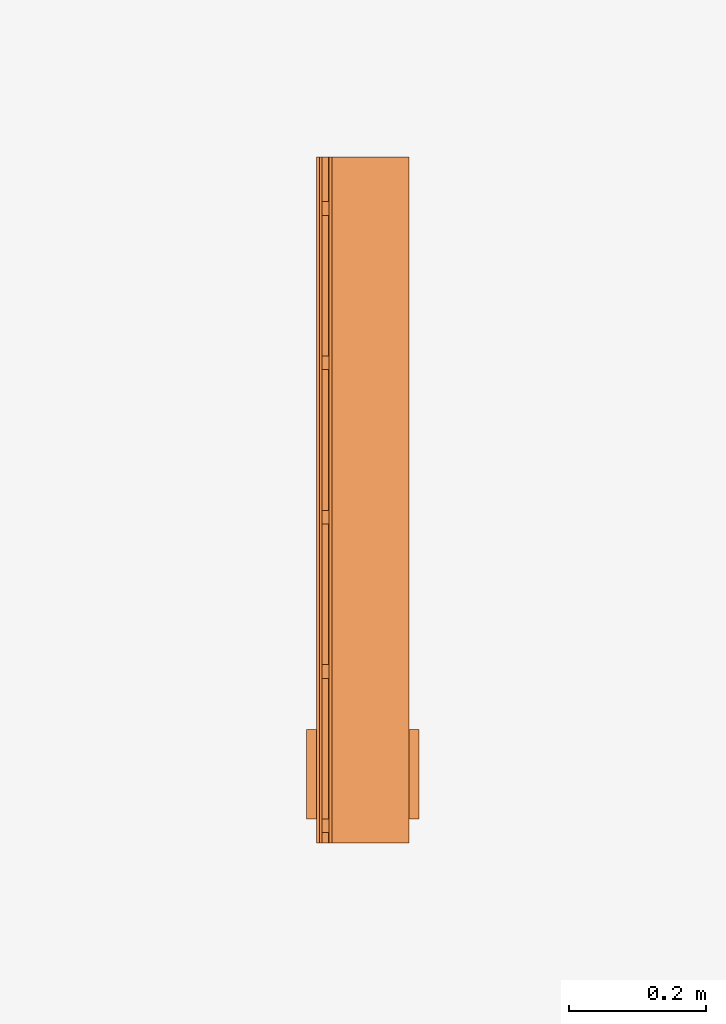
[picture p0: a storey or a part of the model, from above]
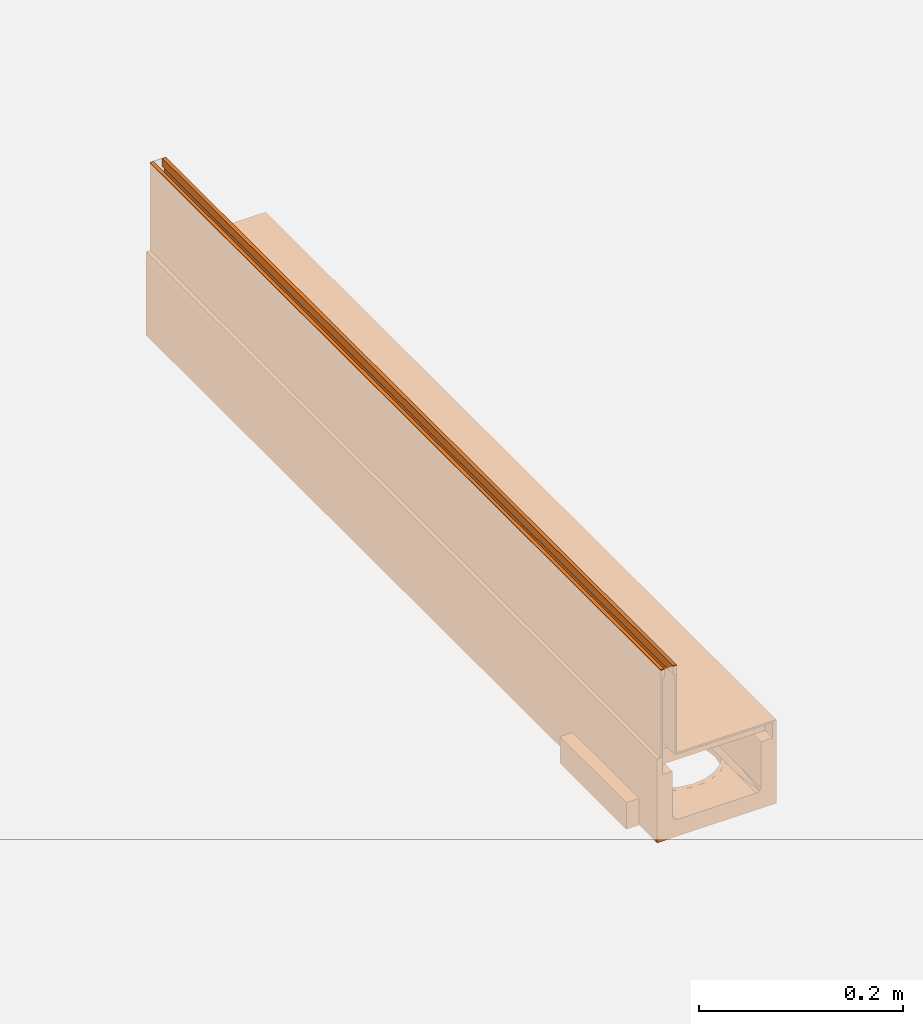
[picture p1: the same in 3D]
Properties of the parts of a building model (IFC2X3)

# File
Description: ViewDefinition [CoordinationView]
File name: 24111.ifc
Time: 2013-10-30T12:03:11
Written by: Autodesk Revit 2013
Made in: 20120221_2030(x64)

# IfcProject, Project Number
LongName: Project Name; Phase: Project Status

# IfcSite, Default
RefLatitude: 42, 21, 30, 344238; RefLongitude: -71, -3, -35, -194702; RefElevation: 0 mm

# IfcBuilding
Pset_BuildingCommon - NumberOfStoreys: 1
Other - Client Name: Owner; Project Issue Date: Issue Date; Project Name: Project Name; Project Status: Project Status; Project Address: ## Street City, State Zip; Project Number: Project Number

# IfcBuildingStorey, Level 1
LongName: Level 1; Elevation: 0 mm
Constraints - Elevation Base: 0; Elevation: 0 mm
Graphics - Line Pattern: Center; Symbol: M_Level Head - Circle: M_Level Head - Circle; Color: 0; Symbol at End 1 Default: no; Line Weight: 1; Symbol at End 2 Default: yes
Identity Data - Structural: no; Building Story: yes; Name: Level 1
Dimensions - Computation Height: 0 mm

# IfcBuildingElementProxy: 24111 - No 0100V Constant Depth Outlet Channel - 1000mm LG - Invert Depth 80mm, Civil-Drainage-Channel-ACO-MultiDrain-M100DS-Brickslot-Channel-System:24111 - No 0100V Constant Depth Outlet Channel - 1000mm LG - Invert Depth 80mm:24111 - No 0100V Constant Depth Outlet Channel - 1000mm LG - Invert Depth 80mm:196059
In: Level 1
Material: Stainless Steel (F), Plastic, Opaque Black, Vienite® Synthetic Resin Concrete
Construction - 23477_Load Class C250 & D400_Brickslot_Access Unit_Stainless Steel_500mm Long: no; 23404_Universal Endcap (Female End): no; 23476_Load Class C250 & D400_Brickslot Grating_Stainless Steel_500mm Long: no; 23475_Load Class C250 & D400_Brickslot Grating_Stainless Steel_1000mm Long: yes; 23404_Universal Endcap (Male End): no; Constant Depth Channel: no; Shallow Depth Channel: no; Constant Depth Junction Channel: no; Shallow Depth Channel with seal: yes; 23410_Sump Unit: no
Phasing - Phase Created: New Construction
Dimensions - EndCap Position: 1000 mm; Volume: 5705977 mm3; Brickslot Void Depth: 0 mm; Brickslot Access Unit Void Depth: -6500 mm; Brickslot Access Unit Void Bottom Depth: -6605 mm; FloorCut_Length: -1000 mm; Length: 1000 mm; Brickslot Void Length: 1000 mm; Custom_Void_length: 0 mm; GratingLength: -1000 mm; Depth: 150 mm; Length Drain: -1000 mm; FloorCut_Depth: 100 mm; FloorCut_Width: 135 mm; Brickslot Access Unit Floor Cut Length: 500 mm; EndCap_Height: 100 mm; InvDepth: 80 mm; ShallowInvDepth: 80 mm; ShallowOverallDepth: 100 mm; Floor Cut Gap: 105 mm
Constraints - Level: Level: Level 1; Moves With Nearby Elements: no
Pset_BuildingElementProxyCommon - Reference: 24111 - No 0100V Constant Depth Outlet Channel - 1000mm LG - Invert Depth 80mm
Data - Product Standard: BS EN 1433:2002, CE marked; ACO Hydraulic Design Software: http://www.acodesign.co.uk; Product Dimensions: 1000mm x 135mm x 100mm (LxWxH); Invert Depth: 80 mm; Installation - Concrete Grade: Refer to brochure; Concrete Surround Volume - Load Class B 125 - C 250 - Concrete Pavement: 0.10m³/m; Hydraulic Performance: http://www.aco.co.uk/download.php?id=173; Pre-formed Outlet Ø: 110mm; Concrete Surround Volume - Load Class A 15 - Concrete Pavement: 0.06m³/m; Load Class: A 15 - D 400; Channel C.S.A: 0.0059m²; Product Weight: 12.4 Kg; Concrete Surround Volume - Load Class D 400 - Concrete Pavement: 0.14m³/m
Identity Data - OmniClass Number: 23.70.50.24; Assembly Code: D2040; e-mail Sales: customersupport@aco.co.uk; Fax: +44 (0)1462 815895; Price: POA - contact ACO; Maintenance guidelines: http://www.aco.co.uk/download.php?id=173; Type Comments: ACO MultiDrain M100DS No 0100V Constant Depth Shallow Outlet Channel 1000mm Long; Product Page URL: http://www.aco.co.uk/product_detail.php?id=58; Address: ACO Business Park, Hitchin Road, Shefford, Bedfordshire, United Kingdom SG17 5TE; e-mail Technical: technical@aco.co.uk; Watermark 1: This file is the property of ACO Technologies PLC; Assembly Description: Rain Water Drainage; URL: www.aco.co.uk; OmniClass Title: Rainwater Removal; Manufacturer: ACO Technologies plc - ACO Water Management Division; Product brochure: http://www.aco.co.uk/download.php?id=173; Watermarked With: BIM Manager Premium Suite; Cost: 0; Model: ACO MultiDrain MDS Brickslot- M100DS; Product Code: 24111; Model Description: Channel drainage system; Watermarked By: www.aco.co.uk; Installation guidelines: http://www.aco.co.uk/download.php?id=173; Watermark 2: This file is water marked and users are prohibited to reproduce, adapt, distribute this information; Telephone: +44 (0)1462 816666
Green Building Properties - Channel Recyclable: Fully recyclable; Channel Recycled Material Content: 20% minimum; Edge Rail Recyclable: Fully recyclable; Edge Rail Recycled Material Content: Between 40% - 90%
Model Properties - Brickslot Grating Product code 23476: Load Class C250/D400 - Brickslot Stainless Steel - 500mm long x 105mm high -10mm Slot- Intake area - 1000mm²/m - 3.3 Kg; Brickslot Grating Product code 23475: Load Class C250/D400 - Brickslot Stainless Steel - 1000mm long x 105mm high -10mm Slot- Intake area - 1000mm²/m - 6.6 Kg; Brickslot Access Unit Product code 23477: Load Class C250/D400 - Brickslot Access Unit Stainless Steel - 500mm long x 105mm high -10mm Slot- Intake area - 1000mm²/m - 6.4 Kg; End Cap Product code 23404: No 306 Universl End Cap - 135mm wide x 300mm long - Spigot Ø110mm x 50mm long - Silver - Polypropylene - 0.16kg
General - SerialNumber: 0; TagNumber: 0
Other - Revision: 1; Created By: www.aco.co.uk
Materials and Finishes - Edge Rail Material: Stainless Steel Grade 304; Edge Rail Colour: Self; Channel Colour: Brown; Channel Material: Vienite® Synthetic Resin Concrete

# IfcOpeningElement: Recess (2)
In: Level 1
Constraints - Room Bounding: yes; Related to Mass: no; Level: Level: Level 1; Height Offset From Level: 0 mm
Structural - Enable Analytical Model: no; Structural: no
Dimensions - Thickness: 400 mm; Perimeter: 20000 mm; Volume: 9984610000 mm3; Area: 25000000 mm2
Phasing - Phase Created: New Construction
Analytical Properties - Absorptance: 0.1; Thermal mass: 543920; Roughness: 1; Thermal Resistance (R): 0.477897; Heat Transfer Coefficient (U): 2.0925
Construction - Default Thickness: 400 mm; Function: 0
Graphics - Coarse Scale Fill Color: 0
Materials and Finishes - Structural Material: Earth

# IfcSlab: Floor:Generic Floor - 400mm, Floor:Generic Floor - 400mm:193825
In: Level 1
PredefinedType: FLOOR; Material: Earth 400 mm
Constraints - Room Bounding: yes; Related to Mass: no; Level: Level: Level 1; Height Offset From Level: 0 mm
Structural - Enable Analytical Model: no; Structural: no
Dimensions - Thickness: 400 mm; Perimeter: 20000 mm; Volume: 9984610000 mm3; Area: 25000000 mm2
Phasing - Phase Created: New Construction
Pset_SlabCommon - Reference: Generic Floor - 400mm; IsExternal: no; LoadBearing: yes
Analytical Properties - Absorptance: 0.1; Thermal mass: 543920; Roughness: 1; Thermal Resistance (R): 0.477897; Heat Transfer Coefficient (U): 2.0925
Construction - Default Thickness: 400 mm; Function: 0
Graphics - Coarse Scale Fill Color: 0
Materials and Finishes - Structural Material: Earth
